# Generated by FakeRAM 2.0
VERSION 5.7 ;
BUSBITCHARS "[]" ;
PROPERTYDEFINITIONS
  MACRO width INTEGER ;
  MACRO depth INTEGER ;
  MACRO banks INTEGER ;
END PROPERTYDEFINITIONS
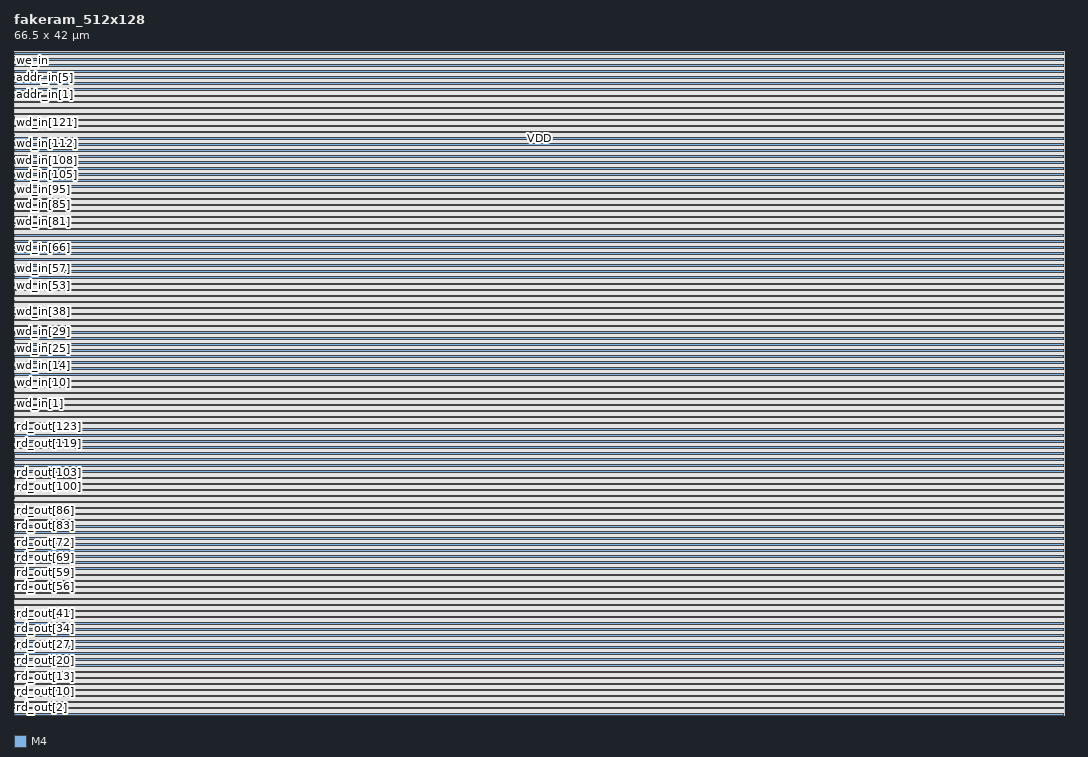
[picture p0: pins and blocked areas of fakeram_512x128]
MACRO fakeram_512x128
  PROPERTY width 128 ;
  PROPERTY depth 512 ;
  PROPERTY banks 4 ;
  FOREIGN fakeram_512x128 0 0 ;
  SYMMETRY X Y R90 ;
  SIZE 66.500 BY 42.000 ;
  CLASS BLOCK ;
  PIN rd_out[0]
    DIRECTION OUTPUT ;
    USE SIGNAL ;
    SHAPE ABUTMENT ;
    PORT
      LAYER M4 ;
      RECT 0.000 0.048 0.024 0.072 ;
    END
  END rd_out[0]
  PIN rd_out[1]
    DIRECTION OUTPUT ;
    USE SIGNAL ;
    SHAPE ABUTMENT ;
    PORT
      LAYER M4 ;
      RECT 0.000 0.192 0.024 0.216 ;
    END
  END rd_out[1]
  PIN rd_out[2]
    DIRECTION OUTPUT ;
    USE SIGNAL ;
    SHAPE ABUTMENT ;
    PORT
      LAYER M4 ;
      RECT 0.000 0.336 0.024 0.360 ;
    END
  END rd_out[2]
  PIN rd_out[3]
    DIRECTION OUTPUT ;
    USE SIGNAL ;
    SHAPE ABUTMENT ;
    PORT
      LAYER M4 ;
      RECT 0.000 0.480 0.024 0.504 ;
    END
  END rd_out[3]
  PIN rd_out[4]
    DIRECTION OUTPUT ;
    USE SIGNAL ;
    SHAPE ABUTMENT ;
    PORT
      LAYER M4 ;
      RECT 0.000 0.624 0.024 0.648 ;
    END
  END rd_out[4]
  PIN rd_out[5]
    DIRECTION OUTPUT ;
    USE SIGNAL ;
    SHAPE ABUTMENT ;
    PORT
      LAYER M4 ;
      RECT 0.000 0.768 0.024 0.792 ;
    END
  END rd_out[5]
  PIN rd_out[6]
    DIRECTION OUTPUT ;
    USE SIGNAL ;
    SHAPE ABUTMENT ;
    PORT
      LAYER M4 ;
      RECT 0.000 0.912 0.024 0.936 ;
    END
  END rd_out[6]
  PIN rd_out[7]
    DIRECTION OUTPUT ;
    USE SIGNAL ;
    SHAPE ABUTMENT ;
    PORT
      LAYER M4 ;
      RECT 0.000 1.056 0.024 1.080 ;
    END
  END rd_out[7]
  PIN rd_out[8]
    DIRECTION OUTPUT ;
    USE SIGNAL ;
    SHAPE ABUTMENT ;
    PORT
      LAYER M4 ;
      RECT 0.000 1.200 0.024 1.224 ;
    END
  END rd_out[8]
  PIN rd_out[9]
    DIRECTION OUTPUT ;
    USE SIGNAL ;
    SHAPE ABUTMENT ;
    PORT
      LAYER M4 ;
      RECT 0.000 1.344 0.024 1.368 ;
    END
  END rd_out[9]
  PIN rd_out[10]
    DIRECTION OUTPUT ;
    USE SIGNAL ;
    SHAPE ABUTMENT ;
    PORT
      LAYER M4 ;
      RECT 0.000 1.488 0.024 1.512 ;
    END
  END rd_out[10]
  PIN rd_out[11]
    DIRECTION OUTPUT ;
    USE SIGNAL ;
    SHAPE ABUTMENT ;
    PORT
      LAYER M4 ;
      RECT 0.000 1.632 0.024 1.656 ;
    END
  END rd_out[11]
  PIN rd_out[12]
    DIRECTION OUTPUT ;
    USE SIGNAL ;
    SHAPE ABUTMENT ;
    PORT
      LAYER M4 ;
      RECT 0.000 1.776 0.024 1.800 ;
    END
  END rd_out[12]
  PIN rd_out[13]
    DIRECTION OUTPUT ;
    USE SIGNAL ;
    SHAPE ABUTMENT ;
    PORT
      LAYER M4 ;
      RECT 0.000 1.920 0.024 1.944 ;
    END
  END rd_out[13]
  PIN rd_out[14]
    DIRECTION OUTPUT ;
    USE SIGNAL ;
    SHAPE ABUTMENT ;
    PORT
      LAYER M4 ;
      RECT 0.000 2.064 0.024 2.088 ;
    END
  END rd_out[14]
  PIN rd_out[15]
    DIRECTION OUTPUT ;
    USE SIGNAL ;
    SHAPE ABUTMENT ;
    PORT
      LAYER M4 ;
      RECT 0.000 2.208 0.024 2.232 ;
    END
  END rd_out[15]
  PIN rd_out[16]
    DIRECTION OUTPUT ;
    USE SIGNAL ;
    SHAPE ABUTMENT ;
    PORT
      LAYER M4 ;
      RECT 0.000 2.352 0.024 2.376 ;
    END
  END rd_out[16]
  PIN rd_out[17]
    DIRECTION OUTPUT ;
    USE SIGNAL ;
    SHAPE ABUTMENT ;
    PORT
      LAYER M4 ;
      RECT 0.000 2.496 0.024 2.520 ;
    END
  END rd_out[17]
  PIN rd_out[18]
    DIRECTION OUTPUT ;
    USE SIGNAL ;
    SHAPE ABUTMENT ;
    PORT
      LAYER M4 ;
      RECT 0.000 2.640 0.024 2.664 ;
    END
  END rd_out[18]
  PIN rd_out[19]
    DIRECTION OUTPUT ;
    USE SIGNAL ;
    SHAPE ABUTMENT ;
    PORT
      LAYER M4 ;
      RECT 0.000 2.784 0.024 2.808 ;
    END
  END rd_out[19]
  PIN rd_out[20]
    DIRECTION OUTPUT ;
    USE SIGNAL ;
    SHAPE ABUTMENT ;
    PORT
      LAYER M4 ;
      RECT 0.000 2.928 0.024 2.952 ;
    END
  END rd_out[20]
  PIN rd_out[21]
    DIRECTION OUTPUT ;
    USE SIGNAL ;
    SHAPE ABUTMENT ;
    PORT
      LAYER M4 ;
      RECT 0.000 3.072 0.024 3.096 ;
    END
  END rd_out[21]
  PIN rd_out[22]
    DIRECTION OUTPUT ;
    USE SIGNAL ;
    SHAPE ABUTMENT ;
    PORT
      LAYER M4 ;
      RECT 0.000 3.216 0.024 3.240 ;
    END
  END rd_out[22]
  PIN rd_out[23]
    DIRECTION OUTPUT ;
    USE SIGNAL ;
    SHAPE ABUTMENT ;
    PORT
      LAYER M4 ;
      RECT 0.000 3.360 0.024 3.384 ;
    END
  END rd_out[23]
  PIN rd_out[24]
    DIRECTION OUTPUT ;
    USE SIGNAL ;
    SHAPE ABUTMENT ;
    PORT
      LAYER M4 ;
      RECT 0.000 3.504 0.024 3.528 ;
    END
  END rd_out[24]
  PIN rd_out[25]
    DIRECTION OUTPUT ;
    USE SIGNAL ;
    SHAPE ABUTMENT ;
    PORT
      LAYER M4 ;
      RECT 0.000 3.648 0.024 3.672 ;
    END
  END rd_out[25]
  PIN rd_out[26]
    DIRECTION OUTPUT ;
    USE SIGNAL ;
    SHAPE ABUTMENT ;
    PORT
      LAYER M4 ;
      RECT 0.000 3.792 0.024 3.816 ;
    END
  END rd_out[26]
  PIN rd_out[27]
    DIRECTION OUTPUT ;
    USE SIGNAL ;
    SHAPE ABUTMENT ;
    PORT
      LAYER M4 ;
      RECT 0.000 3.936 0.024 3.960 ;
    END
  END rd_out[27]
  PIN rd_out[28]
    DIRECTION OUTPUT ;
    USE SIGNAL ;
    SHAPE ABUTMENT ;
    PORT
      LAYER M4 ;
      RECT 0.000 4.080 0.024 4.104 ;
    END
  END rd_out[28]
  PIN rd_out[29]
    DIRECTION OUTPUT ;
    USE SIGNAL ;
    SHAPE ABUTMENT ;
    PORT
      LAYER M4 ;
      RECT 0.000 4.224 0.024 4.248 ;
    END
  END rd_out[29]
  PIN rd_out[30]
    DIRECTION OUTPUT ;
    USE SIGNAL ;
    SHAPE ABUTMENT ;
    PORT
      LAYER M4 ;
      RECT 0.000 4.368 0.024 4.392 ;
    END
  END rd_out[30]
  PIN rd_out[31]
    DIRECTION OUTPUT ;
    USE SIGNAL ;
    SHAPE ABUTMENT ;
    PORT
      LAYER M4 ;
      RECT 0.000 4.512 0.024 4.536 ;
    END
  END rd_out[31]
  PIN rd_out[32]
    DIRECTION OUTPUT ;
    USE SIGNAL ;
    SHAPE ABUTMENT ;
    PORT
      LAYER M4 ;
      RECT 0.000 4.656 0.024 4.680 ;
    END
  END rd_out[32]
  PIN rd_out[33]
    DIRECTION OUTPUT ;
    USE SIGNAL ;
    SHAPE ABUTMENT ;
    PORT
      LAYER M4 ;
      RECT 0.000 4.800 0.024 4.824 ;
    END
  END rd_out[33]
  PIN rd_out[34]
    DIRECTION OUTPUT ;
    USE SIGNAL ;
    SHAPE ABUTMENT ;
    PORT
      LAYER M4 ;
      RECT 0.000 4.944 0.024 4.968 ;
    END
  END rd_out[34]
  PIN rd_out[35]
    DIRECTION OUTPUT ;
    USE SIGNAL ;
    SHAPE ABUTMENT ;
    PORT
      LAYER M4 ;
      RECT 0.000 5.088 0.024 5.112 ;
    END
  END rd_out[35]
  PIN rd_out[36]
    DIRECTION OUTPUT ;
    USE SIGNAL ;
    SHAPE ABUTMENT ;
    PORT
      LAYER M4 ;
      RECT 0.000 5.232 0.024 5.256 ;
    END
  END rd_out[36]
  PIN rd_out[37]
    DIRECTION OUTPUT ;
    USE SIGNAL ;
    SHAPE ABUTMENT ;
    PORT
      LAYER M4 ;
      RECT 0.000 5.376 0.024 5.400 ;
    END
  END rd_out[37]
  PIN rd_out[38]
    DIRECTION OUTPUT ;
    USE SIGNAL ;
    SHAPE ABUTMENT ;
    PORT
      LAYER M4 ;
      RECT 0.000 5.520 0.024 5.544 ;
    END
  END rd_out[38]
  PIN rd_out[39]
    DIRECTION OUTPUT ;
    USE SIGNAL ;
    SHAPE ABUTMENT ;
    PORT
      LAYER M4 ;
      RECT 0.000 5.664 0.024 5.688 ;
    END
  END rd_out[39]
  PIN rd_out[40]
    DIRECTION OUTPUT ;
    USE SIGNAL ;
    SHAPE ABUTMENT ;
    PORT
      LAYER M4 ;
      RECT 0.000 5.808 0.024 5.832 ;
    END
  END rd_out[40]
  PIN rd_out[41]
    DIRECTION OUTPUT ;
    USE SIGNAL ;
    SHAPE ABUTMENT ;
    PORT
      LAYER M4 ;
      RECT 0.000 5.952 0.024 5.976 ;
    END
  END rd_out[41]
  PIN rd_out[42]
    DIRECTION OUTPUT ;
    USE SIGNAL ;
    SHAPE ABUTMENT ;
    PORT
      LAYER M4 ;
      RECT 0.000 6.096 0.024 6.120 ;
    END
  END rd_out[42]
  PIN rd_out[43]
    DIRECTION OUTPUT ;
    USE SIGNAL ;
    SHAPE ABUTMENT ;
    PORT
      LAYER M4 ;
      RECT 0.000 6.240 0.024 6.264 ;
    END
  END rd_out[43]
  PIN rd_out[44]
    DIRECTION OUTPUT ;
    USE SIGNAL ;
    SHAPE ABUTMENT ;
    PORT
      LAYER M4 ;
      RECT 0.000 6.384 0.024 6.408 ;
    END
  END rd_out[44]
  PIN rd_out[45]
    DIRECTION OUTPUT ;
    USE SIGNAL ;
    SHAPE ABUTMENT ;
    PORT
      LAYER M4 ;
      RECT 0.000 6.528 0.024 6.552 ;
    END
  END rd_out[45]
  PIN rd_out[46]
    DIRECTION OUTPUT ;
    USE SIGNAL ;
    SHAPE ABUTMENT ;
    PORT
      LAYER M4 ;
      RECT 0.000 6.672 0.024 6.696 ;
    END
  END rd_out[46]
  PIN rd_out[47]
    DIRECTION OUTPUT ;
    USE SIGNAL ;
    SHAPE ABUTMENT ;
    PORT
      LAYER M4 ;
      RECT 0.000 6.816 0.024 6.840 ;
    END
  END rd_out[47]
  PIN rd_out[48]
    DIRECTION OUTPUT ;
    USE SIGNAL ;
    SHAPE ABUTMENT ;
    PORT
      LAYER M4 ;
      RECT 0.000 6.960 0.024 6.984 ;
    END
  END rd_out[48]
  PIN rd_out[49]
    DIRECTION OUTPUT ;
    USE SIGNAL ;
    SHAPE ABUTMENT ;
    PORT
      LAYER M4 ;
      RECT 0.000 7.104 0.024 7.128 ;
    END
  END rd_out[49]
  PIN rd_out[50]
    DIRECTION OUTPUT ;
    USE SIGNAL ;
    SHAPE ABUTMENT ;
    PORT
      LAYER M4 ;
      RECT 0.000 7.248 0.024 7.272 ;
    END
  END rd_out[50]
  PIN rd_out[51]
    DIRECTION OUTPUT ;
    USE SIGNAL ;
    SHAPE ABUTMENT ;
    PORT
      LAYER M4 ;
      RECT 0.000 7.392 0.024 7.416 ;
    END
  END rd_out[51]
  PIN rd_out[52]
    DIRECTION OUTPUT ;
    USE SIGNAL ;
    SHAPE ABUTMENT ;
    PORT
      LAYER M4 ;
      RECT 0.000 7.536 0.024 7.560 ;
    END
  END rd_out[52]
  PIN rd_out[53]
    DIRECTION OUTPUT ;
    USE SIGNAL ;
    SHAPE ABUTMENT ;
    PORT
      LAYER M4 ;
      RECT 0.000 7.680 0.024 7.704 ;
    END
  END rd_out[53]
  PIN rd_out[54]
    DIRECTION OUTPUT ;
    USE SIGNAL ;
    SHAPE ABUTMENT ;
    PORT
      LAYER M4 ;
      RECT 0.000 7.824 0.024 7.848 ;
    END
  END rd_out[54]
  PIN rd_out[55]
    DIRECTION OUTPUT ;
    USE SIGNAL ;
    SHAPE ABUTMENT ;
    PORT
      LAYER M4 ;
      RECT 0.000 7.968 0.024 7.992 ;
    END
  END rd_out[55]
  PIN rd_out[56]
    DIRECTION OUTPUT ;
    USE SIGNAL ;
    SHAPE ABUTMENT ;
    PORT
      LAYER M4 ;
      RECT 0.000 8.112 0.024 8.136 ;
    END
  END rd_out[56]
  PIN rd_out[57]
    DIRECTION OUTPUT ;
    USE SIGNAL ;
    SHAPE ABUTMENT ;
    PORT
      LAYER M4 ;
      RECT 0.000 8.256 0.024 8.280 ;
    END
  END rd_out[57]
  PIN rd_out[58]
    DIRECTION OUTPUT ;
    USE SIGNAL ;
    SHAPE ABUTMENT ;
    PORT
      LAYER M4 ;
      RECT 0.000 8.400 0.024 8.424 ;
    END
  END rd_out[58]
  PIN rd_out[59]
    DIRECTION OUTPUT ;
    USE SIGNAL ;
    SHAPE ABUTMENT ;
    PORT
      LAYER M4 ;
      RECT 0.000 8.544 0.024 8.568 ;
    END
  END rd_out[59]
  PIN rd_out[60]
    DIRECTION OUTPUT ;
    USE SIGNAL ;
    SHAPE ABUTMENT ;
    PORT
      LAYER M4 ;
      RECT 0.000 8.688 0.024 8.712 ;
    END
  END rd_out[60]
  PIN rd_out[61]
    DIRECTION OUTPUT ;
    USE SIGNAL ;
    SHAPE ABUTMENT ;
    PORT
      LAYER M4 ;
      RECT 0.000 8.832 0.024 8.856 ;
    END
  END rd_out[61]
  PIN rd_out[62]
    DIRECTION OUTPUT ;
    USE SIGNAL ;
    SHAPE ABUTMENT ;
    PORT
      LAYER M4 ;
      RECT 0.000 8.976 0.024 9.000 ;
    END
  END rd_out[62]
  PIN rd_out[63]
    DIRECTION OUTPUT ;
    USE SIGNAL ;
    SHAPE ABUTMENT ;
    PORT
      LAYER M4 ;
      RECT 0.000 9.120 0.024 9.144 ;
    END
  END rd_out[63]
  PIN rd_out[64]
    DIRECTION OUTPUT ;
    USE SIGNAL ;
    SHAPE ABUTMENT ;
    PORT
      LAYER M4 ;
      RECT 0.000 9.264 0.024 9.288 ;
    END
  END rd_out[64]
  PIN rd_out[65]
    DIRECTION OUTPUT ;
    USE SIGNAL ;
    SHAPE ABUTMENT ;
    PORT
      LAYER M4 ;
      RECT 0.000 9.408 0.024 9.432 ;
    END
  END rd_out[65]
  PIN rd_out[66]
    DIRECTION OUTPUT ;
    USE SIGNAL ;
    SHAPE ABUTMENT ;
    PORT
      LAYER M4 ;
      RECT 0.000 9.552 0.024 9.576 ;
    END
  END rd_out[66]
  PIN rd_out[67]
    DIRECTION OUTPUT ;
    USE SIGNAL ;
    SHAPE ABUTMENT ;
    PORT
      LAYER M4 ;
      RECT 0.000 9.696 0.024 9.720 ;
    END
  END rd_out[67]
  PIN rd_out[68]
    DIRECTION OUTPUT ;
    USE SIGNAL ;
    SHAPE ABUTMENT ;
    PORT
      LAYER M4 ;
      RECT 0.000 9.840 0.024 9.864 ;
    END
  END rd_out[68]
  PIN rd_out[69]
    DIRECTION OUTPUT ;
    USE SIGNAL ;
    SHAPE ABUTMENT ;
    PORT
      LAYER M4 ;
      RECT 0.000 9.984 0.024 10.008 ;
    END
  END rd_out[69]
  PIN rd_out[70]
    DIRECTION OUTPUT ;
    USE SIGNAL ;
    SHAPE ABUTMENT ;
    PORT
      LAYER M4 ;
      RECT 0.000 10.128 0.024 10.152 ;
    END
  END rd_out[70]
  PIN rd_out[71]
    DIRECTION OUTPUT ;
    USE SIGNAL ;
    SHAPE ABUTMENT ;
    PORT
      LAYER M4 ;
      RECT 0.000 10.272 0.024 10.296 ;
    END
  END rd_out[71]
  PIN rd_out[72]
    DIRECTION OUTPUT ;
    USE SIGNAL ;
    SHAPE ABUTMENT ;
    PORT
      LAYER M4 ;
      RECT 0.000 10.416 0.024 10.440 ;
    END
  END rd_out[72]
  PIN rd_out[73]
    DIRECTION OUTPUT ;
    USE SIGNAL ;
    SHAPE ABUTMENT ;
    PORT
      LAYER M4 ;
      RECT 0.000 10.560 0.024 10.584 ;
    END
  END rd_out[73]
  PIN rd_out[74]
    DIRECTION OUTPUT ;
    USE SIGNAL ;
    SHAPE ABUTMENT ;
    PORT
      LAYER M4 ;
      RECT 0.000 10.704 0.024 10.728 ;
    END
  END rd_out[74]
  PIN rd_out[75]
    DIRECTION OUTPUT ;
    USE SIGNAL ;
    SHAPE ABUTMENT ;
    PORT
      LAYER M4 ;
      RECT 0.000 10.848 0.024 10.872 ;
    END
  END rd_out[75]
  PIN rd_out[76]
    DIRECTION OUTPUT ;
    USE SIGNAL ;
    SHAPE ABUTMENT ;
    PORT
      LAYER M4 ;
      RECT 0.000 10.992 0.024 11.016 ;
    END
  END rd_out[76]
  PIN rd_out[77]
    DIRECTION OUTPUT ;
    USE SIGNAL ;
    SHAPE ABUTMENT ;
    PORT
      LAYER M4 ;
      RECT 0.000 11.136 0.024 11.160 ;
    END
  END rd_out[77]
  PIN rd_out[78]
    DIRECTION OUTPUT ;
    USE SIGNAL ;
    SHAPE ABUTMENT ;
    PORT
      LAYER M4 ;
      RECT 0.000 11.280 0.024 11.304 ;
    END
  END rd_out[78]
  PIN rd_out[79]
    DIRECTION OUTPUT ;
    USE SIGNAL ;
    SHAPE ABUTMENT ;
    PORT
      LAYER M4 ;
      RECT 0.000 11.424 0.024 11.448 ;
    END
  END rd_out[79]
  PIN rd_out[80]
    DIRECTION OUTPUT ;
    USE SIGNAL ;
    SHAPE ABUTMENT ;
    PORT
      LAYER M4 ;
      RECT 0.000 11.568 0.024 11.592 ;
    END
  END rd_out[80]
  PIN rd_out[81]
    DIRECTION OUTPUT ;
    USE SIGNAL ;
    SHAPE ABUTMENT ;
    PORT
      LAYER M4 ;
      RECT 0.000 11.712 0.024 11.736 ;
    END
  END rd_out[81]
  PIN rd_out[82]
    DIRECTION OUTPUT ;
    USE SIGNAL ;
    SHAPE ABUTMENT ;
    PORT
      LAYER M4 ;
      RECT 0.000 11.856 0.024 11.880 ;
    END
  END rd_out[82]
  PIN rd_out[83]
    DIRECTION OUTPUT ;
    USE SIGNAL ;
    SHAPE ABUTMENT ;
    PORT
      LAYER M4 ;
      RECT 0.000 12.000 0.024 12.024 ;
    END
  END rd_out[83]
  PIN rd_out[84]
    DIRECTION OUTPUT ;
    USE SIGNAL ;
    SHAPE ABUTMENT ;
    PORT
      LAYER M4 ;
      RECT 0.000 12.144 0.024 12.168 ;
    END
  END rd_out[84]
  PIN rd_out[85]
    DIRECTION OUTPUT ;
    USE SIGNAL ;
    SHAPE ABUTMENT ;
    PORT
      LAYER M4 ;
      RECT 0.000 12.288 0.024 12.312 ;
    END
  END rd_out[85]
  PIN rd_out[86]
    DIRECTION OUTPUT ;
    USE SIGNAL ;
    SHAPE ABUTMENT ;
    PORT
      LAYER M4 ;
      RECT 0.000 12.432 0.024 12.456 ;
    END
  END rd_out[86]
  PIN rd_out[87]
    DIRECTION OUTPUT ;
    USE SIGNAL ;
    SHAPE ABUTMENT ;
    PORT
      LAYER M4 ;
      RECT 0.000 12.576 0.024 12.600 ;
    END
  END rd_out[87]
  PIN rd_out[88]
    DIRECTION OUTPUT ;
    USE SIGNAL ;
    SHAPE ABUTMENT ;
    PORT
      LAYER M4 ;
      RECT 0.000 12.720 0.024 12.744 ;
    END
  END rd_out[88]
  PIN rd_out[89]
    DIRECTION OUTPUT ;
    USE SIGNAL ;
    SHAPE ABUTMENT ;
    PORT
      LAYER M4 ;
      RECT 0.000 12.864 0.024 12.888 ;
    END
  END rd_out[89]
  PIN rd_out[90]
    DIRECTION OUTPUT ;
    USE SIGNAL ;
    SHAPE ABUTMENT ;
    PORT
      LAYER M4 ;
      RECT 0.000 13.008 0.024 13.032 ;
    END
  END rd_out[90]
  PIN rd_out[91]
    DIRECTION OUTPUT ;
    USE SIGNAL ;
    SHAPE ABUTMENT ;
    PORT
      LAYER M4 ;
      RECT 0.000 13.152 0.024 13.176 ;
    END
  END rd_out[91]
  PIN rd_out[92]
    DIRECTION OUTPUT ;
    USE SIGNAL ;
    SHAPE ABUTMENT ;
    PORT
      LAYER M4 ;
      RECT 0.000 13.296 0.024 13.320 ;
    END
  END rd_out[92]
  PIN rd_out[93]
    DIRECTION OUTPUT ;
    USE SIGNAL ;
    SHAPE ABUTMENT ;
    PORT
      LAYER M4 ;
      RECT 0.000 13.440 0.024 13.464 ;
    END
  END rd_out[93]
  PIN rd_out[94]
    DIRECTION OUTPUT ;
    USE SIGNAL ;
    SHAPE ABUTMENT ;
    PORT
      LAYER M4 ;
      RECT 0.000 13.584 0.024 13.608 ;
    END
  END rd_out[94]
  PIN rd_out[95]
    DIRECTION OUTPUT ;
    USE SIGNAL ;
    SHAPE ABUTMENT ;
    PORT
      LAYER M4 ;
      RECT 0.000 13.728 0.024 13.752 ;
    END
  END rd_out[95]
  PIN rd_out[96]
    DIRECTION OUTPUT ;
    USE SIGNAL ;
    SHAPE ABUTMENT ;
    PORT
      LAYER M4 ;
      RECT 0.000 13.872 0.024 13.896 ;
    END
  END rd_out[96]
  PIN rd_out[97]
    DIRECTION OUTPUT ;
    USE SIGNAL ;
    SHAPE ABUTMENT ;
    PORT
      LAYER M4 ;
      RECT 0.000 14.016 0.024 14.040 ;
    END
  END rd_out[97]
  PIN rd_out[98]
    DIRECTION OUTPUT ;
    USE SIGNAL ;
    SHAPE ABUTMENT ;
    PORT
      LAYER M4 ;
      RECT 0.000 14.160 0.024 14.184 ;
    END
  END rd_out[98]
  PIN rd_out[99]
    DIRECTION OUTPUT ;
    USE SIGNAL ;
    SHAPE ABUTMENT ;
    PORT
      LAYER M4 ;
      RECT 0.000 14.304 0.024 14.328 ;
    END
  END rd_out[99]
  PIN rd_out[100]
    DIRECTION OUTPUT ;
    USE SIGNAL ;
    SHAPE ABUTMENT ;
    PORT
      LAYER M4 ;
      RECT 0.000 14.448 0.024 14.472 ;
    END
  END rd_out[100]
  PIN rd_out[101]
    DIRECTION OUTPUT ;
    USE SIGNAL ;
    SHAPE ABUTMENT ;
    PORT
      LAYER M4 ;
      RECT 0.000 14.592 0.024 14.616 ;
    END
  END rd_out[101]
  PIN rd_out[102]
    DIRECTION OUTPUT ;
    USE SIGNAL ;
    SHAPE ABUTMENT ;
    PORT
      LAYER M4 ;
      RECT 0.000 14.736 0.024 14.760 ;
    END
  END rd_out[102]
  PIN rd_out[103]
    DIRECTION OUTPUT ;
    USE SIGNAL ;
    SHAPE ABUTMENT ;
    PORT
      LAYER M4 ;
      RECT 0.000 14.880 0.024 14.904 ;
    END
  END rd_out[103]
  PIN rd_out[104]
    DIRECTION OUTPUT ;
    USE SIGNAL ;
    SHAPE ABUTMENT ;
    PORT
      LAYER M4 ;
      RECT 0.000 15.024 0.024 15.048 ;
    END
  END rd_out[104]
  PIN rd_out[105]
    DIRECTION OUTPUT ;
    USE SIGNAL ;
    SHAPE ABUTMENT ;
    PORT
      LAYER M4 ;
      RECT 0.000 15.168 0.024 15.192 ;
    END
  END rd_out[105]
  PIN rd_out[106]
    DIRECTION OUTPUT ;
    USE SIGNAL ;
    SHAPE ABUTMENT ;
    PORT
      LAYER M4 ;
      RECT 0.000 15.312 0.024 15.336 ;
    END
  END rd_out[106]
  PIN rd_out[107]
    DIRECTION OUTPUT ;
    USE SIGNAL ;
    SHAPE ABUTMENT ;
    PORT
      LAYER M4 ;
      RECT 0.000 15.456 0.024 15.480 ;
    END
  END rd_out[107]
  PIN rd_out[108]
    DIRECTION OUTPUT ;
    USE SIGNAL ;
    SHAPE ABUTMENT ;
    PORT
      LAYER M4 ;
      RECT 0.000 15.600 0.024 15.624 ;
    END
  END rd_out[108]
  PIN rd_out[109]
    DIRECTION OUTPUT ;
    USE SIGNAL ;
    SHAPE ABUTMENT ;
    PORT
      LAYER M4 ;
      RECT 0.000 15.744 0.024 15.768 ;
    END
  END rd_out[109]
  PIN rd_out[110]
    DIRECTION OUTPUT ;
    USE SIGNAL ;
    SHAPE ABUTMENT ;
    PORT
      LAYER M4 ;
      RECT 0.000 15.888 0.024 15.912 ;
    END
  END rd_out[110]
  PIN rd_out[111]
    DIRECTION OUTPUT ;
    USE SIGNAL ;
    SHAPE ABUTMENT ;
    PORT
      LAYER M4 ;
      RECT 0.000 16.032 0.024 16.056 ;
    END
  END rd_out[111]
  PIN rd_out[112]
    DIRECTION OUTPUT ;
    USE SIGNAL ;
    SHAPE ABUTMENT ;
    PORT
      LAYER M4 ;
      RECT 0.000 16.176 0.024 16.200 ;
    END
  END rd_out[112]
  PIN rd_out[113]
    DIRECTION OUTPUT ;
    USE SIGNAL ;
    SHAPE ABUTMENT ;
    PORT
      LAYER M4 ;
      RECT 0.000 16.320 0.024 16.344 ;
    END
  END rd_out[113]
  PIN rd_out[114]
    DIRECTION OUTPUT ;
    USE SIGNAL ;
    SHAPE ABUTMENT ;
    PORT
      LAYER M4 ;
      RECT 0.000 16.464 0.024 16.488 ;
    END
  END rd_out[114]
  PIN rd_out[115]
    DIRECTION OUTPUT ;
    USE SIGNAL ;
    SHAPE ABUTMENT ;
    PORT
      LAYER M4 ;
      RECT 0.000 16.608 0.024 16.632 ;
    END
  END rd_out[115]
  PIN rd_out[116]
    DIRECTION OUTPUT ;
    USE SIGNAL ;
    SHAPE ABUTMENT ;
    PORT
      LAYER M4 ;
      RECT 0.000 16.752 0.024 16.776 ;
    END
  END rd_out[116]
  PIN rd_out[117]
    DIRECTION OUTPUT ;
    USE SIGNAL ;
    SHAPE ABUTMENT ;
    PORT
      LAYER M4 ;
      RECT 0.000 16.896 0.024 16.920 ;
    END
  END rd_out[117]
  PIN rd_out[118]
    DIRECTION OUTPUT ;
    USE SIGNAL ;
    SHAPE ABUTMENT ;
    PORT
      LAYER M4 ;
      RECT 0.000 17.040 0.024 17.064 ;
    END
  END rd_out[118]
  PIN rd_out[119]
    DIRECTION OUTPUT ;
    USE SIGNAL ;
    SHAPE ABUTMENT ;
    PORT
      LAYER M4 ;
      RECT 0.000 17.184 0.024 17.208 ;
    END
  END rd_out[119]
  PIN rd_out[120]
    DIRECTION OUTPUT ;
    USE SIGNAL ;
    SHAPE ABUTMENT ;
    PORT
      LAYER M4 ;
      RECT 0.000 17.328 0.024 17.352 ;
    END
  END rd_out[120]
  PIN rd_out[121]
    DIRECTION OUTPUT ;
    USE SIGNAL ;
    SHAPE ABUTMENT ;
    PORT
      LAYER M4 ;
      RECT 0.000 17.472 0.024 17.496 ;
    END
  END rd_out[121]
  PIN rd_out[122]
    DIRECTION OUTPUT ;
    USE SIGNAL ;
    SHAPE ABUTMENT ;
    PORT
      LAYER M4 ;
      RECT 0.000 17.616 0.024 17.640 ;
    END
  END rd_out[122]
  PIN rd_out[123]
    DIRECTION OUTPUT ;
    USE SIGNAL ;
    SHAPE ABUTMENT ;
    PORT
      LAYER M4 ;
      RECT 0.000 17.760 0.024 17.784 ;
    END
  END rd_out[123]
  PIN rd_out[124]
    DIRECTION OUTPUT ;
    USE SIGNAL ;
    SHAPE ABUTMENT ;
    PORT
      LAYER M4 ;
      RECT 0.000 17.904 0.024 17.928 ;
    END
  END rd_out[124]
  PIN rd_out[125]
    DIRECTION OUTPUT ;
    USE SIGNAL ;
    SHAPE ABUTMENT ;
    PORT
      LAYER M4 ;
      RECT 0.000 18.048 0.024 18.072 ;
    END
  END rd_out[125]
  PIN rd_out[126]
    DIRECTION OUTPUT ;
    USE SIGNAL ;
    SHAPE ABUTMENT ;
    PORT
      LAYER M4 ;
      RECT 0.000 18.192 0.024 18.216 ;
    END
  END rd_out[126]
  PIN rd_out[127]
    DIRECTION OUTPUT ;
    USE SIGNAL ;
    SHAPE ABUTMENT ;
    PORT
      LAYER M4 ;
      RECT 0.000 18.336 0.024 18.360 ;
    END
  END rd_out[127]
  PIN wd_in[0]
    DIRECTION INPUT ;
    USE SIGNAL ;
    SHAPE ABUTMENT ;
    PORT
      LAYER M4 ;
      RECT 0.000 19.584 0.024 19.608 ;
    END
  END wd_in[0]
  PIN wd_in[1]
    DIRECTION INPUT ;
    USE SIGNAL ;
    SHAPE ABUTMENT ;
    PORT
      LAYER M4 ;
      RECT 0.000 19.728 0.024 19.752 ;
    END
  END wd_in[1]
  PIN wd_in[2]
    DIRECTION INPUT ;
    USE SIGNAL ;
    SHAPE ABUTMENT ;
    PORT
      LAYER M4 ;
      RECT 0.000 19.872 0.024 19.896 ;
    END
  END wd_in[2]
  PIN wd_in[3]
    DIRECTION INPUT ;
    USE SIGNAL ;
    SHAPE ABUTMENT ;
    PORT
      LAYER M4 ;
      RECT 0.000 20.016 0.024 20.040 ;
    END
  END wd_in[3]
  PIN wd_in[4]
    DIRECTION INPUT ;
    USE SIGNAL ;
    SHAPE ABUTMENT ;
    PORT
      LAYER M4 ;
      RECT 0.000 20.160 0.024 20.184 ;
    END
  END wd_in[4]
  PIN wd_in[5]
    DIRECTION INPUT ;
    USE SIGNAL ;
    SHAPE ABUTMENT ;
    PORT
      LAYER M4 ;
      RECT 0.000 20.304 0.024 20.328 ;
    END
  END wd_in[5]
  PIN wd_in[6]
    DIRECTION INPUT ;
    USE SIGNAL ;
    SHAPE ABUTMENT ;
    PORT
      LAYER M4 ;
      RECT 0.000 20.448 0.024 20.472 ;
    END
  END wd_in[6]
  PIN wd_in[7]
    DIRECTION INPUT ;
    USE SIGNAL ;
    SHAPE ABUTMENT ;
    PORT
      LAYER M4 ;
      RECT 0.000 20.592 0.024 20.616 ;
    END
  END wd_in[7]
  PIN wd_in[8]
    DIRECTION INPUT ;
    USE SIGNAL ;
    SHAPE ABUTMENT ;
    PORT
      LAYER M4 ;
      RECT 0.000 20.736 0.024 20.760 ;
    END
  END wd_in[8]
  PIN wd_in[9]
    DIRECTION INPUT ;
    USE SIGNAL ;
    SHAPE ABUTMENT ;
    PORT
      LAYER M4 ;
      RECT 0.000 20.880 0.024 20.904 ;
    END
  END wd_in[9]
  PIN wd_in[10]
    DIRECTION INPUT ;
    USE SIGNAL ;
    SHAPE ABUTMENT ;
    PORT
      LAYER M4 ;
      RECT 0.000 21.024 0.024 21.048 ;
    END
  END wd_in[10]
  PIN wd_in[11]
    DIRECTION INPUT ;
    USE SIGNAL ;
    SHAPE ABUTMENT ;
    PORT
      LAYER M4 ;
      RECT 0.000 21.168 0.024 21.192 ;
    END
  END wd_in[11]
  PIN wd_in[12]
    DIRECTION INPUT ;
    USE SIGNAL ;
    SHAPE ABUTMENT ;
    PORT
      LAYER M4 ;
      RECT 0.000 21.312 0.024 21.336 ;
    END
  END wd_in[12]
  PIN wd_in[13]
    DIRECTION INPUT ;
    USE SIGNAL ;
    SHAPE ABUTMENT ;
    PORT
      LAYER M4 ;
      RECT 0.000 21.456 0.024 21.480 ;
    END
  END wd_in[13]
  PIN wd_in[14]
    DIRECTION INPUT ;
    USE SIGNAL ;
    SHAPE ABUTMENT ;
    PORT
      LAYER M4 ;
      RECT 0.000 21.600 0.024 21.624 ;
    END
  END wd_in[14]
  PIN wd_in[15]
    DIRECTION INPUT ;
    USE SIGNAL ;
    SHAPE ABUTMENT ;
    PORT
      LAYER M4 ;
      RECT 0.000 21.744 0.024 21.768 ;
    END
  END wd_in[15]
  PIN wd_in[16]
    DIRECTION INPUT ;
    USE SIGNAL ;
    SHAPE ABUTMENT ;
    PORT
      LAYER M4 ;
      RECT 0.000 21.888 0.024 21.912 ;
    END
  END wd_in[16]
  PIN wd_in[17]
    DIRECTION INPUT ;
    USE SIGNAL ;
    SHAPE ABUTMENT ;
    PORT
      LAYER M4 ;
      RECT 0.000 22.032 0.024 22.056 ;
    END
  END wd_in[17]
  PIN wd_in[18]
    DIRECTION INPUT ;
    USE SIGNAL ;
    SHAPE ABUTMENT ;
    PORT
      LAYER M4 ;
      RECT 0.000 22.176 0.024 22.200 ;
    END
  END wd_in[18]
  PIN wd_in[19]
    DIRECTION INPUT ;
    USE SIGNAL ;
    SHAPE ABUTMENT ;
    PORT
      LAYER M4 ;
      RECT 0.000 22.320 0.024 22.344 ;
    END
  END wd_in[19]
  PIN wd_in[20]
    DIRECTION INPUT ;
    USE SIGNAL ;
    SHAPE ABUTMENT ;
    PORT
      LAYER M4 ;
      RECT 0.000 22.464 0.024 22.488 ;
    END
  END wd_in[20]
  PIN wd_in[21]
    DIRECTION INPUT ;
    USE SIGNAL ;
    SHAPE ABUTMENT ;
    PORT
      LAYER M4 ;
      RECT 0.000 22.608 0.024 22.632 ;
    END
  END wd_in[21]
  PIN wd_in[22]
    DIRECTION INPUT ;
    USE SIGNAL ;
    SHAPE ABUTMENT ;
    PORT
      LAYER M4 ;
      RECT 0.000 22.752 0.024 22.776 ;
    END
  END wd_in[22]
  PIN wd_in[23]
    DIRECTION INPUT ;
    USE SIGNAL ;
    SHAPE ABUTMENT ;
    PORT
      LAYER M4 ;
      RECT 0.000 22.896 0.024 22.920 ;
    END
  END wd_in[23]
  PIN wd_in[24]
    DIRECTION INPUT ;
    USE SIGNAL ;
    SHAPE ABUTMENT ;
    PORT
      LAYER M4 ;
      RECT 0.000 23.040 0.024 23.064 ;
    END
  END wd_in[24]
  PIN wd_in[25]
    DIRECTION INPUT ;
    USE SIGNAL ;
    SHAPE ABUTMENT ;
    PORT
      LAYER M4 ;
      RECT 0.000 23.184 0.024 23.208 ;
    END
  END wd_in[25]
  PIN wd_in[26]
    DIRECTION INPUT ;
    USE SIGNAL ;
    SHAPE ABUTMENT ;
    PORT
      LAYER M4 ;
      RECT 0.000 23.328 0.024 23.352 ;
    END
  END wd_in[26]
  PIN wd_in[27]
    DIRECTION INPUT ;
    USE SIGNAL ;
    SHAPE ABUTMENT ;
    PORT
      LAYER M4 ;
      RECT 0.000 23.472 0.024 23.496 ;
    END
  END wd_in[27]
  PIN wd_in[28]
    DIRECTION INPUT ;
    USE SIGNAL ;
    SHAPE ABUTMENT ;
    PORT
      LAYER M4 ;
      RECT 0.000 23.616 0.024 23.640 ;
    END
  END wd_in[28]
  PIN wd_in[29]
    DIRECTION INPUT ;
    USE SIGNAL ;
    SHAPE ABUTMENT ;
    PORT
      LAYER M4 ;
      RECT 0.000 23.760 0.024 23.784 ;
    END
  END wd_in[29]
  PIN wd_in[30]
    DIRECTION INPUT ;
    USE SIGNAL ;
    SHAPE ABUTMENT ;
    PORT
      LAYER M4 ;
      RECT 0.000 23.904 0.024 23.928 ;
    END
  END wd_in[30]
  PIN wd_in[31]
    DIRECTION INPUT ;
    USE SIGNAL ;
    SHAPE ABUTMENT ;
    PORT
      LAYER M4 ;
      RECT 0.000 24.048 0.024 24.072 ;
    END
  END wd_in[31]
  PIN wd_in[32]
    DIRECTION INPUT ;
    USE SIGNAL ;
    SHAPE ABUTMENT ;
    PORT
      LAYER M4 ;
      RECT 0.000 24.192 0.024 24.216 ;
    END
  END wd_in[32]
  PIN wd_in[33]
    DIRECTION INPUT ;
    USE SIGNAL ;
    SHAPE ABUTMENT ;
    PORT
      LAYER M4 ;
      RECT 0.000 24.336 0.024 24.360 ;
    END
  END wd_in[33]
  PIN wd_in[34]
    DIRECTION INPUT ;
    USE SIGNAL ;
    SHAPE ABUTMENT ;
    PORT
      LAYER M4 ;
      RECT 0.000 24.480 0.024 24.504 ;
    END
  END wd_in[34]
  PIN wd_in[35]
    DIRECTION INPUT ;
    USE SIGNAL ;
    SHAPE ABUTMENT ;
    PORT
      LAYER M4 ;
      RECT 0.000 24.624 0.024 24.648 ;
    END
  END wd_in[35]
  PIN wd_in[36]
    DIRECTION INPUT ;
    USE SIGNAL ;
    SHAPE ABUTMENT ;
    PORT
      LAYER M4 ;
      RECT 0.000 24.768 0.024 24.792 ;
    END
  END wd_in[36]
  PIN wd_in[37]
    DIRECTION INPUT ;
    USE SIGNAL ;
    SHAPE ABUTMENT ;
    PORT
      LAYER M4 ;
      RECT 0.000 24.912 0.024 24.936 ;
    END
  END wd_in[37]
  PIN wd_in[38]
    DIRECTION INPUT ;
    USE SIGNAL ;
    SHAPE ABUTMENT ;
    PORT
      LAYER M4 ;
      RECT 0.000 25.056 0.024 25.080 ;
    END
  END wd_in[38]
  PIN wd_in[39]
    DIRECTION INPUT ;
    USE SIGNAL ;
    SHAPE ABUTMENT ;
    PORT
      LAYER M4 ;
      RECT 0.000 25.200 0.024 25.224 ;
    END
  END wd_in[39]
  PIN wd_in[40]
    DIRECTION INPUT ;
    USE SIGNAL ;
    SHAPE ABUTMENT ;
    PORT
      LAYER M4 ;
      RECT 0.000 25.344 0.024 25.368 ;
    END
  END wd_in[40]
  PIN wd_in[41]
    DIRECTION INPUT ;
    USE SIGNAL ;
    SHAPE ABUTMENT ;
    PORT
      LAYER M4 ;
      RECT 0.000 25.488 0.024 25.512 ;
    END
  END wd_in[41]
  PIN wd_in[42]
    DIRECTION INPUT ;
    USE SIGNAL ;
    SHAPE ABUTMENT ;
    PORT
      LAYER M4 ;
      RECT 0.000 25.632 0.024 25.656 ;
    END
  END wd_in[42]
  PIN wd_in[43]
    DIRECTION INPUT ;
    USE SIGNAL ;
    SHAPE ABUTMENT ;
    PORT
      LAYER M4 ;
      RECT 0.000 25.776 0.024 25.800 ;
    END
  END wd_in[43]
  PIN wd_in[44]
    DIRECTION INPUT ;
    USE SIGNAL ;
    SHAPE ABUTMENT ;
    PORT
      LAYER M4 ;
      RECT 0.000 25.920 0.024 25.944 ;
    END
  END wd_in[44]
  PIN wd_in[45]
    DIRECTION INPUT ;
    USE SIGNAL ;
    SHAPE ABUTMENT ;
    PORT
      LAYER M4 ;
      RECT 0.000 26.064 0.024 26.088 ;
    END
  END wd_in[45]
  PIN wd_in[46]
    DIRECTION INPUT ;
    USE SIGNAL ;
    SHAPE ABUTMENT ;
    PORT
      LAYER M4 ;
      RECT 0.000 26.208 0.024 26.232 ;
    END
  END wd_in[46]
  PIN wd_in[47]
    DIRECTION INPUT ;
    USE SIGNAL ;
    SHAPE ABUTMENT ;
    PORT
      LAYER M4 ;
      RECT 0.000 26.352 0.024 26.376 ;
    END
  END wd_in[47]
  PIN wd_in[48]
    DIRECTION INPUT ;
    USE SIGNAL ;
    SHAPE ABUTMENT ;
    PORT
      LAYER M4 ;
      RECT 0.000 26.496 0.024 26.520 ;
    END
  END wd_in[48]
  PIN wd_in[49]
    DIRECTION INPUT ;
    USE SIGNAL ;
    SHAPE ABUTMENT ;
    PORT
      LAYER M4 ;
      RECT 0.000 26.640 0.024 26.664 ;
    END
  END wd_in[49]
  PIN wd_in[50]
    DIRECTION INPUT ;
    USE SIGNAL ;
    SHAPE ABUTMENT ;
    PORT
      LAYER M4 ;
      RECT 0.000 26.784 0.024 26.808 ;
    END
  END wd_in[50]
  PIN wd_in[51]
    DIRECTION INPUT ;
    USE SIGNAL ;
    SHAPE ABUTMENT ;
    PORT
      LAYER M4 ;
      RECT 0.000 26.928 0.024 26.952 ;
    END
  END wd_in[51]
  PIN wd_in[52]
    DIRECTION INPUT ;
    USE SIGNAL ;
    SHAPE ABUTMENT ;
    PORT
      LAYER M4 ;
      RECT 0.000 27.072 0.024 27.096 ;
    END
  END wd_in[52]
  PIN wd_in[53]
    DIRECTION INPUT ;
    USE SIGNAL ;
    SHAPE ABUTMENT ;
    PORT
      LAYER M4 ;
      RECT 0.000 27.216 0.024 27.240 ;
    END
  END wd_in[53]
  PIN wd_in[54]
    DIRECTION INPUT ;
    USE SIGNAL ;
    SHAPE ABUTMENT ;
    PORT
      LAYER M4 ;
      RECT 0.000 27.360 0.024 27.384 ;
    END
  END wd_in[54]
  PIN wd_in[55]
    DIRECTION INPUT ;
    USE SIGNAL ;
    SHAPE ABUTMENT ;
    PORT
      LAYER M4 ;
      RECT 0.000 27.504 0.024 27.528 ;
    END
  END wd_in[55]
  PIN wd_in[56]
    DIRECTION INPUT ;
    USE SIGNAL ;
    SHAPE ABUTMENT ;
    PORT
      LAYER M4 ;
      RECT 0.000 27.648 0.024 27.672 ;
    END
  END wd_in[56]
  PIN wd_in[57]
    DIRECTION INPUT ;
    USE SIGNAL ;
    SHAPE ABUTMENT ;
    PORT
      LAYER M4 ;
      RECT 0.000 27.792 0.024 27.816 ;
    END
  END wd_in[57]
  PIN wd_in[58]
    DIRECTION INPUT ;
    USE SIGNAL ;
    SHAPE ABUTMENT ;
    PORT
      LAYER M4 ;
      RECT 0.000 27.936 0.024 27.960 ;
    END
  END wd_in[58]
  PIN wd_in[59]
    DIRECTION INPUT ;
    USE SIGNAL ;
    SHAPE ABUTMENT ;
    PORT
      LAYER M4 ;
      RECT 0.000 28.080 0.024 28.104 ;
    END
  END wd_in[59]
  PIN wd_in[60]
    DIRECTION INPUT ;
    USE SIGNAL ;
    SHAPE ABUTMENT ;
    PORT
      LAYER M4 ;
      RECT 0.000 28.224 0.024 28.248 ;
    END
  END wd_in[60]
  PIN wd_in[61]
    DIRECTION INPUT ;
    USE SIGNAL ;
    SHAPE ABUTMENT ;
    PORT
      LAYER M4 ;
      RECT 0.000 28.368 0.024 28.392 ;
    END
  END wd_in[61]
  PIN wd_in[62]
    DIRECTION INPUT ;
    USE SIGNAL ;
    SHAPE ABUTMENT ;
    PORT
      LAYER M4 ;
      RECT 0.000 28.512 0.024 28.536 ;
    END
  END wd_in[62]
  PIN wd_in[63]
    DIRECTION INPUT ;
    USE SIGNAL ;
    SHAPE ABUTMENT ;
    PORT
      LAYER M4 ;
      RECT 0.000 28.656 0.024 28.680 ;
    END
  END wd_in[63]
  PIN wd_in[64]
    DIRECTION INPUT ;
    USE SIGNAL ;
    SHAPE ABUTMENT ;
    PORT
      LAYER M4 ;
      RECT 0.000 28.800 0.024 28.824 ;
    END
  END wd_in[64]
  PIN wd_in[65]
    DIRECTION INPUT ;
    USE SIGNAL ;
    SHAPE ABUTMENT ;
    PORT
      LAYER M4 ;
      RECT 0.000 28.944 0.024 28.968 ;
    END
  END wd_in[65]
  PIN wd_in[66]
    DIRECTION INPUT ;
    USE SIGNAL ;
    SHAPE ABUTMENT ;
    PORT
      LAYER M4 ;
      RECT 0.000 29.088 0.024 29.112 ;
    END
  END wd_in[66]
  PIN wd_in[67]
    DIRECTION INPUT ;
    USE SIGNAL ;
    SHAPE ABUTMENT ;
    PORT
      LAYER M4 ;
      RECT 0.000 29.232 0.024 29.256 ;
    END
  END wd_in[67]
  PIN wd_in[68]
    DIRECTION INPUT ;
    USE SIGNAL ;
    SHAPE ABUTMENT ;
    PORT
      LAYER M4 ;
      RECT 0.000 29.376 0.024 29.400 ;
    END
  END wd_in[68]
  PIN wd_in[69]
    DIRECTION INPUT ;
    USE SIGNAL ;
    SHAPE ABUTMENT ;
    PORT
      LAYER M4 ;
      RECT 0.000 29.520 0.024 29.544 ;
    END
  END wd_in[69]
  PIN wd_in[70]
    DIRECTION INPUT ;
    USE SIGNAL ;
    SHAPE ABUTMENT ;
    PORT
      LAYER M4 ;
      RECT 0.000 29.664 0.024 29.688 ;
    END
  END wd_in[70]
  PIN wd_in[71]
    DIRECTION INPUT ;
    USE SIGNAL ;
    SHAPE ABUTMENT ;
    PORT
      LAYER M4 ;
      RECT 0.000 29.808 0.024 29.832 ;
    END
  END wd_in[71]
  PIN wd_in[72]
    DIRECTION INPUT ;
    USE SIGNAL ;
    SHAPE ABUTMENT ;
    PORT
      LAYER M4 ;
      RECT 0.000 29.952 0.024 29.976 ;
    END
  END wd_in[72]
  PIN wd_in[73]
    DIRECTION INPUT ;
    USE SIGNAL ;
    SHAPE ABUTMENT ;
    PORT
      LAYER M4 ;
      RECT 0.000 30.096 0.024 30.120 ;
    END
  END wd_in[73]
  PIN wd_in[74]
    DIRECTION INPUT ;
    USE SIGNAL ;
    SHAPE ABUTMENT ;
    PORT
      LAYER M4 ;
      RECT 0.000 30.240 0.024 30.264 ;
    END
  END wd_in[74]
  PIN wd_in[75]
    DIRECTION INPUT ;
    USE SIGNAL ;
    SHAPE ABUTMENT ;
    PORT
      LAYER M4 ;
      RECT 0.000 30.384 0.024 30.408 ;
    END
  END wd_in[75]
  PIN wd_in[76]
    DIRECTION INPUT ;
    USE SIGNAL ;
    SHAPE ABUTMENT ;
    PORT
      LAYER M4 ;
      RECT 0.000 30.528 0.024 30.552 ;
    END
  END wd_in[76]
  PIN wd_in[77]
    DIRECTION INPUT ;
    USE SIGNAL ;
    SHAPE ABUTMENT ;
    PORT
      LAYER M4 ;
      RECT 0.000 30.672 0.024 30.696 ;
    END
  END wd_in[77]
  PIN wd_in[78]
    DIRECTION INPUT ;
    USE SIGNAL ;
    SHAPE ABUTMENT ;
    PORT
      LAYER M4 ;
      RECT 0.000 30.816 0.024 30.840 ;
    END
  END wd_in[78]
  PIN wd_in[79]
    DIRECTION INPUT ;
    USE SIGNAL ;
    SHAPE ABUTMENT ;
    PORT
      LAYER M4 ;
      RECT 0.000 30.960 0.024 30.984 ;
    END
  END wd_in[79]
  PIN wd_in[80]
    DIRECTION INPUT ;
    USE SIGNAL ;
    SHAPE ABUTMENT ;
    PORT
      LAYER M4 ;
      RECT 0.000 31.104 0.024 31.128 ;
    END
  END wd_in[80]
  PIN wd_in[81]
    DIRECTION INPUT ;
    USE SIGNAL ;
    SHAPE ABUTMENT ;
    PORT
      LAYER M4 ;
      RECT 0.000 31.248 0.024 31.272 ;
    END
  END wd_in[81]
  PIN wd_in[82]
    DIRECTION INPUT ;
    USE SIGNAL ;
    SHAPE ABUTMENT ;
    PORT
      LAYER M4 ;
      RECT 0.000 31.392 0.024 31.416 ;
    END
  END wd_in[82]
  PIN wd_in[83]
    DIRECTION INPUT ;
    USE SIGNAL ;
    SHAPE ABUTMENT ;
    PORT
      LAYER M4 ;
      RECT 0.000 31.536 0.024 31.560 ;
    END
  END wd_in[83]
  PIN wd_in[84]
    DIRECTION INPUT ;
    USE SIGNAL ;
    SHAPE ABUTMENT ;
    PORT
      LAYER M4 ;
      RECT 0.000 31.680 0.024 31.704 ;
    END
  END wd_in[84]
  PIN wd_in[85]
    DIRECTION INPUT ;
    USE SIGNAL ;
    SHAPE ABUTMENT ;
    PORT
      LAYER M4 ;
      RECT 0.000 31.824 0.024 31.848 ;
    END
  END wd_in[85]
  PIN wd_in[86]
    DIRECTION INPUT ;
    USE SIGNAL ;
    SHAPE ABUTMENT ;
    PORT
      LAYER M4 ;
      RECT 0.000 31.968 0.024 31.992 ;
    END
  END wd_in[86]
  PIN wd_in[87]
    DIRECTION INPUT ;
    USE SIGNAL ;
    SHAPE ABUTMENT ;
    PORT
      LAYER M4 ;
      RECT 0.000 32.112 0.024 32.136 ;
    END
  END wd_in[87]
  PIN wd_in[88]
    DIRECTION INPUT ;
    USE SIGNAL ;
    SHAPE ABUTMENT ;
    PORT
      LAYER M4 ;
      RECT 0.000 32.256 0.024 32.280 ;
    END
  END wd_in[88]
  PIN wd_in[89]
    DIRECTION INPUT ;
    USE SIGNAL ;
    SHAPE ABUTMENT ;
    PORT
      LAYER M4 ;
      RECT 0.000 32.400 0.024 32.424 ;
    END
  END wd_in[89]
  PIN wd_in[90]
    DIRECTION INPUT ;
    USE SIGNAL ;
    SHAPE ABUTMENT ;
    PORT
      LAYER M4 ;
      RECT 0.000 32.544 0.024 32.568 ;
    END
  END wd_in[90]
  PIN wd_in[91]
    DIRECTION INPUT ;
    USE SIGNAL ;
    SHAPE ABUTMENT ;
    PORT
      LAYER M4 ;
      RECT 0.000 32.688 0.024 32.712 ;
    END
  END wd_in[91]
  PIN wd_in[92]
    DIRECTION INPUT ;
    USE SIGNAL ;
    SHAPE ABUTMENT ;
    PORT
      LAYER M4 ;
      RECT 0.000 32.832 0.024 32.856 ;
    END
  END wd_in[92]
  PIN wd_in[93]
    DIRECTION INPUT ;
    USE SIGNAL ;
    SHAPE ABUTMENT ;
    PORT
      LAYER M4 ;
      RECT 0.000 32.976 0.024 33.000 ;
    END
  END wd_in[93]
  PIN wd_in[94]
    DIRECTION INPUT ;
    USE SIGNAL ;
    SHAPE ABUTMENT ;
    PORT
      LAYER M4 ;
      RECT 0.000 33.120 0.024 33.144 ;
    END
  END wd_in[94]
  PIN wd_in[95]
    DIRECTION INPUT ;
    USE SIGNAL ;
    SHAPE ABUTMENT ;
    PORT
      LAYER M4 ;
      RECT 0.000 33.264 0.024 33.288 ;
    END
  END wd_in[95]
  PIN wd_in[96]
    DIRECTION INPUT ;
    USE SIGNAL ;
    SHAPE ABUTMENT ;
    PORT
      LAYER M4 ;
      RECT 0.000 33.408 0.024 33.432 ;
    END
  END wd_in[96]
  PIN wd_in[97]
    DIRECTION INPUT ;
    USE SIGNAL ;
    SHAPE ABUTMENT ;
    PORT
      LAYER M4 ;
      RECT 0.000 33.552 0.024 33.576 ;
    END
  END wd_in[97]
  PIN wd_in[98]
    DIRECTION INPUT ;
    USE SIGNAL ;
    SHAPE ABUTMENT ;
    PORT
      LAYER M4 ;
      RECT 0.000 33.696 0.024 33.720 ;
    END
  END wd_in[98]
  PIN wd_in[99]
    DIRECTION INPUT ;
    USE SIGNAL ;
    SHAPE ABUTMENT ;
    PORT
      LAYER M4 ;
      RECT 0.000 33.840 0.024 33.864 ;
    END
  END wd_in[99]
  PIN wd_in[100]
    DIRECTION INPUT ;
    USE SIGNAL ;
    SHAPE ABUTMENT ;
    PORT
      LAYER M4 ;
      RECT 0.000 33.984 0.024 34.008 ;
    END
  END wd_in[100]
  PIN wd_in[101]
    DIRECTION INPUT ;
    USE SIGNAL ;
    SHAPE ABUTMENT ;
    PORT
      LAYER M4 ;
      RECT 0.000 34.128 0.024 34.152 ;
    END
  END wd_in[101]
  PIN wd_in[102]
    DIRECTION INPUT ;
    USE SIGNAL ;
    SHAPE ABUTMENT ;
    PORT
      LAYER M4 ;
      RECT 0.000 34.272 0.024 34.296 ;
    END
  END wd_in[102]
  PIN wd_in[103]
    DIRECTION INPUT ;
    USE SIGNAL ;
    SHAPE ABUTMENT ;
    PORT
      LAYER M4 ;
      RECT 0.000 34.416 0.024 34.440 ;
    END
  END wd_in[103]
  PIN wd_in[104]
    DIRECTION INPUT ;
    USE SIGNAL ;
    SHAPE ABUTMENT ;
    PORT
      LAYER M4 ;
      RECT 0.000 34.560 0.024 34.584 ;
    END
  END wd_in[104]
  PIN wd_in[105]
    DIRECTION INPUT ;
    USE SIGNAL ;
    SHAPE ABUTMENT ;
    PORT
      LAYER M4 ;
      RECT 0.000 34.704 0.024 34.728 ;
    END
  END wd_in[105]
  PIN wd_in[106]
    DIRECTION INPUT ;
    USE SIGNAL ;
    SHAPE ABUTMENT ;
    PORT
      LAYER M4 ;
      RECT 0.000 34.848 0.024 34.872 ;
    END
  END wd_in[106]
  PIN wd_in[107]
    DIRECTION INPUT ;
    USE SIGNAL ;
    SHAPE ABUTMENT ;
    PORT
      LAYER M4 ;
      RECT 0.000 34.992 0.024 35.016 ;
    END
  END wd_in[107]
  PIN wd_in[108]
    DIRECTION INPUT ;
    USE SIGNAL ;
    SHAPE ABUTMENT ;
    PORT
      LAYER M4 ;
      RECT 0.000 35.136 0.024 35.160 ;
    END
  END wd_in[108]
  PIN wd_in[109]
    DIRECTION INPUT ;
    USE SIGNAL ;
    SHAPE ABUTMENT ;
    PORT
      LAYER M4 ;
      RECT 0.000 35.280 0.024 35.304 ;
    END
  END wd_in[109]
  PIN wd_in[110]
    DIRECTION INPUT ;
    USE SIGNAL ;
    SHAPE ABUTMENT ;
    PORT
      LAYER M4 ;
      RECT 0.000 35.424 0.024 35.448 ;
    END
  END wd_in[110]
  PIN wd_in[111]
    DIRECTION INPUT ;
    USE SIGNAL ;
    SHAPE ABUTMENT ;
    PORT
      LAYER M4 ;
      RECT 0.000 35.568 0.024 35.592 ;
    END
  END wd_in[111]
  PIN wd_in[112]
    DIRECTION INPUT ;
    USE SIGNAL ;
    SHAPE ABUTMENT ;
    PORT
      LAYER M4 ;
      RECT 0.000 35.712 0.024 35.736 ;
    END
  END wd_in[112]
  PIN wd_in[113]
    DIRECTION INPUT ;
    USE SIGNAL ;
    SHAPE ABUTMENT ;
    PORT
      LAYER M4 ;
      RECT 0.000 35.856 0.024 35.880 ;
    END
  END wd_in[113]
  PIN wd_in[114]
    DIRECTION INPUT ;
    USE SIGNAL ;
    SHAPE ABUTMENT ;
    PORT
      LAYER M4 ;
      RECT 0.000 36.000 0.024 36.024 ;
    END
  END wd_in[114]
  PIN wd_in[115]
    DIRECTION INPUT ;
    USE SIGNAL ;
    SHAPE ABUTMENT ;
    PORT
      LAYER M4 ;
      RECT 0.000 36.144 0.024 36.168 ;
    END
  END wd_in[115]
  PIN wd_in[116]
    DIRECTION INPUT ;
    USE SIGNAL ;
    SHAPE ABUTMENT ;
    PORT
      LAYER M4 ;
      RECT 0.000 36.288 0.024 36.312 ;
    END
  END wd_in[116]
  PIN wd_in[117]
    DIRECTION INPUT ;
    USE SIGNAL ;
    SHAPE ABUTMENT ;
    PORT
      LAYER M4 ;
      RECT 0.000 36.432 0.024 36.456 ;
    END
  END wd_in[117]
  PIN wd_in[118]
    DIRECTION INPUT ;
    USE SIGNAL ;
    SHAPE ABUTMENT ;
    PORT
      LAYER M4 ;
      RECT 0.000 36.576 0.024 36.600 ;
    END
  END wd_in[118]
  PIN wd_in[119]
    DIRECTION INPUT ;
    USE SIGNAL ;
    SHAPE ABUTMENT ;
    PORT
      LAYER M4 ;
      RECT 0.000 36.720 0.024 36.744 ;
    END
  END wd_in[119]
  PIN wd_in[120]
    DIRECTION INPUT ;
    USE SIGNAL ;
    SHAPE ABUTMENT ;
    PORT
      LAYER M4 ;
      RECT 0.000 36.864 0.024 36.888 ;
    END
  END wd_in[120]
  PIN wd_in[121]
    DIRECTION INPUT ;
    USE SIGNAL ;
    SHAPE ABUTMENT ;
    PORT
      LAYER M4 ;
      RECT 0.000 37.008 0.024 37.032 ;
    END
  END wd_in[121]
  PIN wd_in[122]
    DIRECTION INPUT ;
    USE SIGNAL ;
    SHAPE ABUTMENT ;
    PORT
      LAYER M4 ;
      RECT 0.000 37.152 0.024 37.176 ;
    END
  END wd_in[122]
  PIN wd_in[123]
    DIRECTION INPUT ;
    USE SIGNAL ;
    SHAPE ABUTMENT ;
    PORT
      LAYER M4 ;
      RECT 0.000 37.296 0.024 37.320 ;
    END
  END wd_in[123]
  PIN wd_in[124]
    DIRECTION INPUT ;
    USE SIGNAL ;
    SHAPE ABUTMENT ;
    PORT
      LAYER M4 ;
      RECT 0.000 37.440 0.024 37.464 ;
    END
  END wd_in[124]
  PIN wd_in[125]
    DIRECTION INPUT ;
    USE SIGNAL ;
    SHAPE ABUTMENT ;
    PORT
      LAYER M4 ;
      RECT 0.000 37.584 0.024 37.608 ;
    END
  END wd_in[125]
  PIN wd_in[126]
    DIRECTION INPUT ;
    USE SIGNAL ;
    SHAPE ABUTMENT ;
    PORT
      LAYER M4 ;
      RECT 0.000 37.728 0.024 37.752 ;
    END
  END wd_in[126]
  PIN wd_in[127]
    DIRECTION INPUT ;
    USE SIGNAL ;
    SHAPE ABUTMENT ;
    PORT
      LAYER M4 ;
      RECT 0.000 37.872 0.024 37.896 ;
    END
  END wd_in[127]
  PIN addr_in[0]
    DIRECTION INPUT ;
    USE SIGNAL ;
    SHAPE ABUTMENT ;
    PORT
      LAYER M4 ;
      RECT 0.000 39.120 0.024 39.144 ;
    END
  END addr_in[0]
  PIN addr_in[1]
    DIRECTION INPUT ;
    USE SIGNAL ;
    SHAPE ABUTMENT ;
    PORT
      LAYER M4 ;
      RECT 0.000 39.264 0.024 39.288 ;
    END
  END addr_in[1]
  PIN addr_in[2]
    DIRECTION INPUT ;
    USE SIGNAL ;
    SHAPE ABUTMENT ;
    PORT
      LAYER M4 ;
      RECT 0.000 39.408 0.024 39.432 ;
    END
  END addr_in[2]
  PIN addr_in[3]
    DIRECTION INPUT ;
    USE SIGNAL ;
    SHAPE ABUTMENT ;
    PORT
      LAYER M4 ;
      RECT 0.000 39.552 0.024 39.576 ;
    END
  END addr_in[3]
  PIN addr_in[4]
    DIRECTION INPUT ;
    USE SIGNAL ;
    SHAPE ABUTMENT ;
    PORT
      LAYER M4 ;
      RECT 0.000 39.696 0.024 39.720 ;
    END
  END addr_in[4]
  PIN addr_in[5]
    DIRECTION INPUT ;
    USE SIGNAL ;
    SHAPE ABUTMENT ;
    PORT
      LAYER M4 ;
      RECT 0.000 39.840 0.024 39.864 ;
    END
  END addr_in[5]
  PIN addr_in[6]
    DIRECTION INPUT ;
    USE SIGNAL ;
    SHAPE ABUTMENT ;
    PORT
      LAYER M4 ;
      RECT 0.000 39.984 0.024 40.008 ;
    END
  END addr_in[6]
  PIN addr_in[7]
    DIRECTION INPUT ;
    USE SIGNAL ;
    SHAPE ABUTMENT ;
    PORT
      LAYER M4 ;
      RECT 0.000 40.128 0.024 40.152 ;
    END
  END addr_in[7]
  PIN addr_in[8]
    DIRECTION INPUT ;
    USE SIGNAL ;
    SHAPE ABUTMENT ;
    PORT
      LAYER M4 ;
      RECT 0.000 40.272 0.024 40.296 ;
    END
  END addr_in[8]
  PIN we_in
    DIRECTION INPUT ;
    USE SIGNAL ;
    SHAPE ABUTMENT ;
    PORT
      LAYER M4 ;
      RECT 0.000 41.520 0.024 41.544 ;
    END
  END we_in
  PIN clk
    DIRECTION INPUT ;
    USE SIGNAL ;
    SHAPE ABUTMENT ;
    PORT
      LAYER M4 ;
      RECT 0.000 41.664 0.024 41.688 ;
    END
  END clk
  PIN ce_in
    DIRECTION INPUT ;
    USE SIGNAL ;
    SHAPE ABUTMENT ;
    PORT
      LAYER M4 ;
      RECT 0.000 41.808 0.024 41.832 ;
    END
  END ce_in
  PIN VDD
    DIRECTION INOUT ;
    USE POWER ;
    PORT
      LAYER M4 ;
      RECT 0.048 0.384 66.452 0.480 ;
      RECT 0.048 1.152 66.452 1.248 ;
      RECT 0.048 1.920 66.452 2.016 ;
      RECT 0.048 2.688 66.452 2.784 ;
      RECT 0.048 3.456 66.452 3.552 ;
      RECT 0.048 4.224 66.452 4.320 ;
      RECT 0.048 4.992 66.452 5.088 ;
      RECT 0.048 5.760 66.452 5.856 ;
      RECT 0.048 6.528 66.452 6.624 ;
      RECT 0.048 7.296 66.452 7.392 ;
      RECT 0.048 8.064 66.452 8.160 ;
      RECT 0.048 8.832 66.452 8.928 ;
      RECT 0.048 9.600 66.452 9.696 ;
      RECT 0.048 10.368 66.452 10.464 ;
      RECT 0.048 11.136 66.452 11.232 ;
      RECT 0.048 11.904 66.452 12.000 ;
      RECT 0.048 12.672 66.452 12.768 ;
      RECT 0.048 13.440 66.452 13.536 ;
      RECT 0.048 14.208 66.452 14.304 ;
      RECT 0.048 14.976 66.452 15.072 ;
      RECT 0.048 15.744 66.452 15.840 ;
      RECT 0.048 16.512 66.452 16.608 ;
      RECT 0.048 17.280 66.452 17.376 ;
      RECT 0.048 18.048 66.452 18.144 ;
      RECT 0.048 18.816 66.452 18.912 ;
      RECT 0.048 19.584 66.452 19.680 ;
      RECT 0.048 20.352 66.452 20.448 ;
      RECT 0.048 21.120 66.452 21.216 ;
      RECT 0.048 21.888 66.452 21.984 ;
      RECT 0.048 22.656 66.452 22.752 ;
      RECT 0.048 23.424 66.452 23.520 ;
      RECT 0.048 24.192 66.452 24.288 ;
      RECT 0.048 24.960 66.452 25.056 ;
      RECT 0.048 25.728 66.452 25.824 ;
      RECT 0.048 26.496 66.452 26.592 ;
      RECT 0.048 27.264 66.452 27.360 ;
      RECT 0.048 28.032 66.452 28.128 ;
      RECT 0.048 28.800 66.452 28.896 ;
      RECT 0.048 29.568 66.452 29.664 ;
      RECT 0.048 30.336 66.452 30.432 ;
      RECT 0.048 31.104 66.452 31.200 ;
      RECT 0.048 31.872 66.452 31.968 ;
      RECT 0.048 32.640 66.452 32.736 ;
      RECT 0.048 33.408 66.452 33.504 ;
      RECT 0.048 34.176 66.452 34.272 ;
      RECT 0.048 34.944 66.452 35.040 ;
      RECT 0.048 35.712 66.452 35.808 ;
      RECT 0.048 36.480 66.452 36.576 ;
      RECT 0.048 37.248 66.452 37.344 ;
      RECT 0.048 38.016 66.452 38.112 ;
      RECT 0.048 38.784 66.452 38.880 ;
      RECT 0.048 39.552 66.452 39.648 ;
      RECT 0.048 40.320 66.452 40.416 ;
      RECT 0.048 41.088 66.452 41.184 ;
      RECT 0.048 41.856 66.452 41.952 ;
    END
  END VDD
  PIN VSS
    DIRECTION INOUT ;
    USE GROUND ;
    PORT
      LAYER M4 ;
      RECT 0.048 0.000 66.452 0.096 ;
      RECT 0.048 0.768 66.452 0.864 ;
      RECT 0.048 1.536 66.452 1.632 ;
      RECT 0.048 2.304 66.452 2.400 ;
      RECT 0.048 3.072 66.452 3.168 ;
      RECT 0.048 3.840 66.452 3.936 ;
      RECT 0.048 4.608 66.452 4.704 ;
      RECT 0.048 5.376 66.452 5.472 ;
      RECT 0.048 6.144 66.452 6.240 ;
      RECT 0.048 6.912 66.452 7.008 ;
      RECT 0.048 7.680 66.452 7.776 ;
      RECT 0.048 8.448 66.452 8.544 ;
      RECT 0.048 9.216 66.452 9.312 ;
      RECT 0.048 9.984 66.452 10.080 ;
      RECT 0.048 10.752 66.452 10.848 ;
      RECT 0.048 11.520 66.452 11.616 ;
      RECT 0.048 12.288 66.452 12.384 ;
      RECT 0.048 13.056 66.452 13.152 ;
      RECT 0.048 13.824 66.452 13.920 ;
      RECT 0.048 14.592 66.452 14.688 ;
      RECT 0.048 15.360 66.452 15.456 ;
      RECT 0.048 16.128 66.452 16.224 ;
      RECT 0.048 16.896 66.452 16.992 ;
      RECT 0.048 17.664 66.452 17.760 ;
      RECT 0.048 18.432 66.452 18.528 ;
      RECT 0.048 19.200 66.452 19.296 ;
      RECT 0.048 19.968 66.452 20.064 ;
      RECT 0.048 20.736 66.452 20.832 ;
      RECT 0.048 21.504 66.452 21.600 ;
      RECT 0.048 22.272 66.452 22.368 ;
      RECT 0.048 23.040 66.452 23.136 ;
      RECT 0.048 23.808 66.452 23.904 ;
      RECT 0.048 24.576 66.452 24.672 ;
      RECT 0.048 25.344 66.452 25.440 ;
      RECT 0.048 26.112 66.452 26.208 ;
      RECT 0.048 26.880 66.452 26.976 ;
      RECT 0.048 27.648 66.452 27.744 ;
      RECT 0.048 28.416 66.452 28.512 ;
      RECT 0.048 29.184 66.452 29.280 ;
      RECT 0.048 29.952 66.452 30.048 ;
      RECT 0.048 30.720 66.452 30.816 ;
      RECT 0.048 31.488 66.452 31.584 ;
      RECT 0.048 32.256 66.452 32.352 ;
      RECT 0.048 33.024 66.452 33.120 ;
      RECT 0.048 33.792 66.452 33.888 ;
      RECT 0.048 34.560 66.452 34.656 ;
      RECT 0.048 35.328 66.452 35.424 ;
      RECT 0.048 36.096 66.452 36.192 ;
      RECT 0.048 36.864 66.452 36.960 ;
      RECT 0.048 37.632 66.452 37.728 ;
      RECT 0.048 38.400 66.452 38.496 ;
      RECT 0.048 39.168 66.452 39.264 ;
      RECT 0.048 39.936 66.452 40.032 ;
      RECT 0.048 40.704 66.452 40.800 ;
      RECT 0.048 41.472 66.452 41.568 ;
    END
  END VSS
  OBS
    LAYER M1 ;
    RECT 0 0 66.500 42.000 ;
    LAYER M2 ;
    RECT 0 0 66.500 42.000 ;
    LAYER M3 ;
    RECT 0 0 66.500 42.000 ;
    LAYER M4 ;
    RECT 0 0 66.500 42.000 ;
  END
END fakeram_512x128

END LIBRARY
